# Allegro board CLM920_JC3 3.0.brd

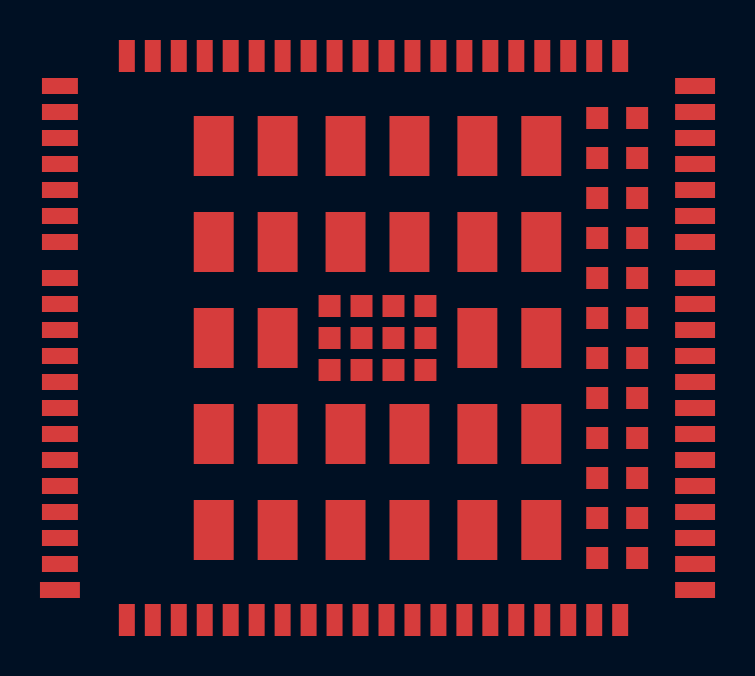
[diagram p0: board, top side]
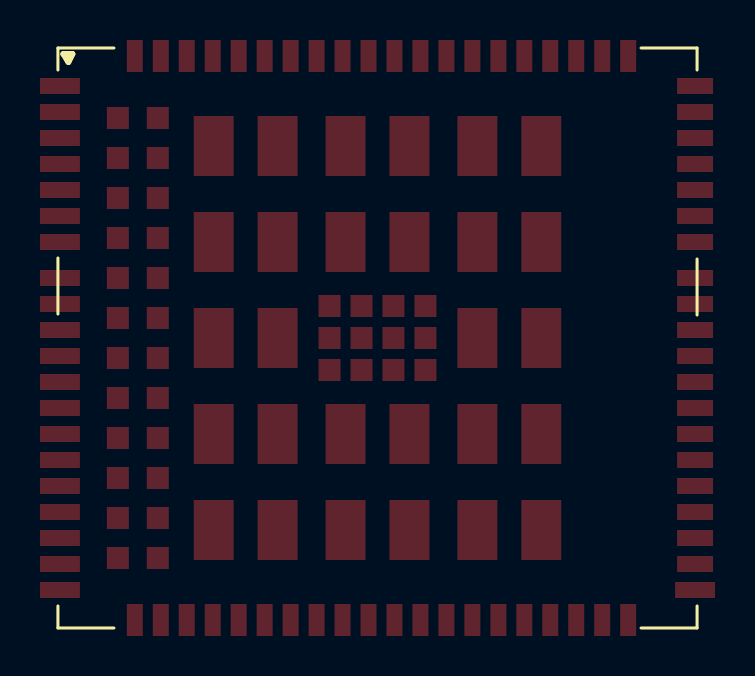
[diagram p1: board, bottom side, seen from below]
No outline. copper layers: TOP, BOTTOM. Coordinates in mm from the lowest, leftmost part position.

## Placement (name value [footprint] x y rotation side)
U1  -  [IF_LCC_144P_DEMO]  0 0 0 top

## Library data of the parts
U1 = IF_LCC_144P_DEMO

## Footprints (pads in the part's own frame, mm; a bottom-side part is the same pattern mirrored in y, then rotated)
IF_LCC_144P_DEMO
  rect 2x0.8 smd: 1(15.9,12.6) 2(15.9,11.3) 3(15.9,10) 4(15.9,8.7) 5(15.9,7.4) 6(15.9,6.1) 7(15.9,4.8) 8(15.9,0.4) 9(15.9,-0.9) 10(15.9,-2.2) 11(15.9,-3.5) 12(15.9,-4.8) 13(15.9,-6.1) 14(15.9,-7.4) 15(15.9,-8.7) 16(15.9,-10) 17(15.9,-11.3) 18(15.9,-12.6) 37(-15.9,-12.6) 141(15.9,3) 142(15.9,1.7)
  rect 0.8x1.6 smd: 19(9.55,-14.1) 20(8.25,-14.1) 21(6.95,-14.1) 22(5.65,-14.1) 23(4.35,-14.1) 24(3.05,-14.1) 25(1.75,-14.1) 26(0.45,-14.1) 27(-0.85,-14.1) 28(-2.15,-14.1) 29(-3.45,-14.1) 30(-4.75,-14.1) 31(-6.05,-14.1) 32(-7.35,-14.1) 33(-8.65,-14.1) 34(-9.95,-14.1) 35(-11.25,-14.1) 36(-12.55,-14.1) 55(-12.55,14.1) 56(-11.25,14.1) 57(-9.95,14.1) 58(-8.65,14.1) 59(-7.35,14.1) 60(-6.05,14.1) 61(-4.75,14.1) 62(-3.45,14.1) 63(-2.15,14.1) 64(-0.85,14.1) 65(0.45,14.1) 66(1.75,14.1) 67(3.05,14.1) 68(4.35,14.1) 69(5.65,14.1) 70(6.95,14.1) 71(8.25,14.1) 72(9.55,14.1) 113(10.85,14.1) 114(12.15,14.1) 115(10.85,-14.1) 116(12.15,-14.1)
  rect 1.8x0.8 smd: 38(-15.9,-11.3) 39(-15.9,-10) 40(-15.9,-8.7) 41(-15.9,-7.4) 42(-15.9,-6.1) 43(-15.9,-4.8) 44(-15.9,-3.5) 45(-15.9,-2.2) 46(-15.9,-0.9) 47(-15.9,0.4) 48(-15.9,4.8) 49(-15.9,6.1) 50(-15.9,7.4) 51(-15.9,8.7) 52(-15.9,10) 53(-15.9,11.3) 54(-15.9,12.6) 143(-15.9,3) 144(-15.9,1.7)
  rect 1.1x1.1 smd: 73(-2.4,1.6) 74(-2.4,0) 75(-2.4,-1.6) 76(-0.8,1.6) 77(-0.8,0) 78(-0.8,-1.6) 79(0.8,1.6) 80(0.8,0) 81(0.8,-1.6) 82(2.4,1.6) 83(2.4,0) 84(2.4,-1.6) 117(11,11) 118(11,9) 119(11,7) 120(11,5) 121(11,3) 122(11,1) 123(11,-1) 124(11,-3) 125(11,-5) 126(11,-7) 127(11,-9) 128(11,-11) 129(13,11) 130(13,9) 131(13,7) 132(13,5) 133(13,3) 134(13,1) 135(13,-1) 136(13,-3) 137(13,-5) 138(13,-7) 139(13,-9) 140(13,-11)
  rect 2x3 smd: 85(-8.2,9.6) 86(-8.2,4.8) 87(-8.2,0) 88(-8.2,-4.8) 89(-8.2,-9.6) 90(-5,9.6) 91(-5,4.8) 92(-5,0) 93(-5,-4.8) 94(-5,-9.6) 95(-1.6,9.6) 96(-1.6,4.8) 97(-1.6,-4.8) 98(-1.6,-9.6) 99(1.6,9.6) 100(1.6,4.8) 101(1.6,-4.8) 102(1.6,-9.6) 103(5,9.6) 104(5,4.8) 105(5,0) 106(5,-4.8) 107(5,-9.6) 108(8.2,9.6) 109(8.2,4.8) 110(8.2,0) 111(8.2,-4.8) 112(8.2,-9.6)

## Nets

Pads without a net: U1 1 2 3 4 5 6 7 8 9 10 11 12 13 14 15 16 17 18 19 20 21 22 23 24 25 26 27 28 29 30 31 32 33 34 35 36 37 38 39 40 41 42 43 44 45 46 47 48 49 50 51 52 53 54 55 56 57 58 59 60 61 62 63 64 65 66 67 68 69 70 71 72 73 74 75 76 77 78 79 80 81 82 83 84 85 86 87 88 89 90 91 92 93 94 95 96 97 98 99 100 101 102 103 104 105 106 107 108 109 110 111 112 113 114 115 116 117 118 119 120 121 122 123 124 125 126 127 128 129 130 131 132 133 134 135 136 137 138 139 140 141 142 143 144
